VERSION 5.7 ;
  NOWIREEXTENSIONATPIN ON ;
  DIVIDERCHAR "/" ;
  BUSBITCHARS "[]" ;
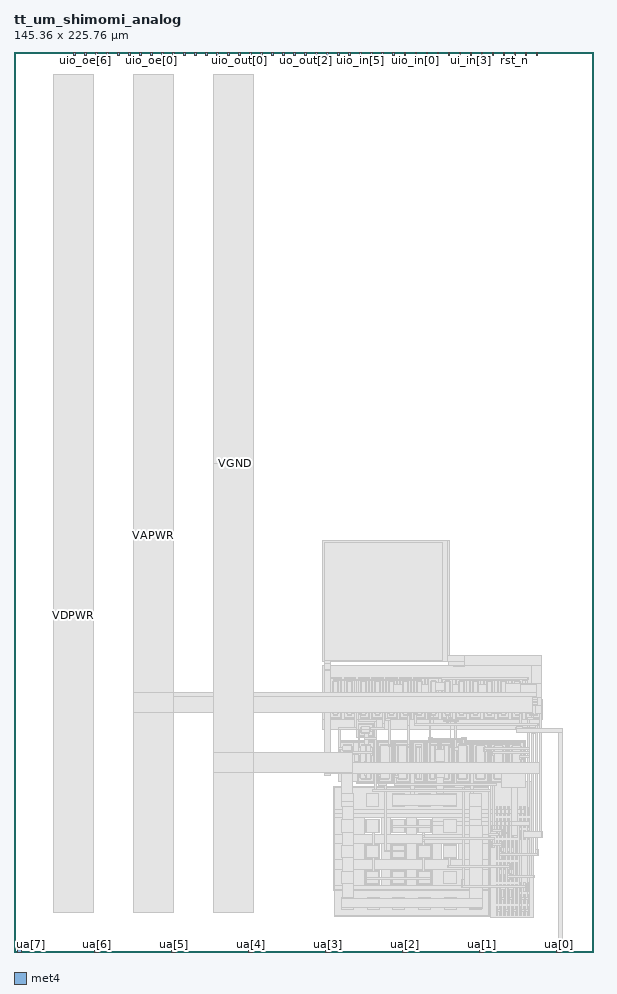
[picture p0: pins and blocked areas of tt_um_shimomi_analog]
MACRO tt_um_shimomi_analog
  CLASS BLOCK ;
  FOREIGN tt_um_shimomi_analog ;
  ORIGIN 0.000 0.000 ;
  SIZE 145.360 BY 225.760 ;
  PIN clk
    DIRECTION INPUT ;
    USE SIGNAL ;
    PORT
      LAYER met4 ;
        RECT 128.190 224.760 128.490 225.760 ;
    END
  END clk
  PIN ena
    DIRECTION INPUT ;
    USE SIGNAL ;
    PORT
      LAYER met4 ;
        RECT 130.950 224.760 131.250 225.760 ;
    END
  END ena
  PIN rst_n
    DIRECTION INPUT ;
    USE SIGNAL ;
    PORT
      LAYER met4 ;
        RECT 125.430 224.760 125.730 225.760 ;
    END
  END rst_n
  PIN ua[0]
    DIRECTION INOUT ;
    USE SIGNAL ;
    ANTENNADIFFAREA 11.599999 ;
    PORT
      LAYER met4 ;
        RECT 136.170 0.000 137.070 1.000 ;
    END
  END ua[0]
  PIN ua[1]
    DIRECTION INOUT ;
    USE SIGNAL ;
    PORT
      LAYER met4 ;
        RECT 116.850 0.000 117.750 1.000 ;
    END
  END ua[1]
  PIN ua[2]
    DIRECTION INOUT ;
    USE SIGNAL ;
    PORT
      LAYER met4 ;
        RECT 97.530 0.000 98.430 1.000 ;
    END
  END ua[2]
  PIN ua[3]
    DIRECTION INOUT ;
    USE SIGNAL ;
    PORT
      LAYER met4 ;
        RECT 78.210 0.000 79.110 1.000 ;
    END
  END ua[3]
  PIN ua[4]
    DIRECTION INOUT ;
    USE SIGNAL ;
    PORT
      LAYER met4 ;
        RECT 58.890 0.000 59.790 1.000 ;
    END
  END ua[4]
  PIN ua[5]
    DIRECTION INOUT ;
    USE SIGNAL ;
    PORT
      LAYER met4 ;
        RECT 39.570 0.000 40.470 1.000 ;
    END
  END ua[5]
  PIN ua[6]
    DIRECTION INOUT ;
    USE SIGNAL ;
    PORT
      LAYER met4 ;
        RECT 20.250 0.000 21.150 1.000 ;
    END
  END ua[6]
  PIN ua[7]
    DIRECTION INOUT ;
    USE SIGNAL ;
    PORT
      LAYER met4 ;
        RECT 0.930 0.000 1.830 1.000 ;
    END
  END ua[7]
  PIN ui_in[0]
    DIRECTION INPUT ;
    USE SIGNAL ;
    PORT
      LAYER met4 ;
        RECT 122.670 224.760 122.970 225.760 ;
    END
  END ui_in[0]
  PIN ui_in[1]
    DIRECTION INPUT ;
    USE SIGNAL ;
    PORT
      LAYER met4 ;
        RECT 119.910 224.760 120.210 225.760 ;
    END
  END ui_in[1]
  PIN ui_in[2]
    DIRECTION INPUT ;
    USE SIGNAL ;
    PORT
      LAYER met4 ;
        RECT 117.150 224.760 117.450 225.760 ;
    END
  END ui_in[2]
  PIN ui_in[3]
    DIRECTION INPUT ;
    USE SIGNAL ;
    PORT
      LAYER met4 ;
        RECT 114.390 224.760 114.690 225.760 ;
    END
  END ui_in[3]
  PIN ui_in[4]
    DIRECTION INPUT ;
    USE SIGNAL ;
    PORT
      LAYER met4 ;
        RECT 111.630 224.760 111.930 225.760 ;
    END
  END ui_in[4]
  PIN ui_in[5]
    DIRECTION INPUT ;
    USE SIGNAL ;
    PORT
      LAYER met4 ;
        RECT 108.870 224.760 109.170 225.760 ;
    END
  END ui_in[5]
  PIN ui_in[6]
    DIRECTION INPUT ;
    USE SIGNAL ;
    PORT
      LAYER met4 ;
        RECT 106.110 224.760 106.410 225.760 ;
    END
  END ui_in[6]
  PIN ui_in[7]
    DIRECTION INPUT ;
    USE SIGNAL ;
    PORT
      LAYER met4 ;
        RECT 103.350 224.760 103.650 225.760 ;
    END
  END ui_in[7]
  PIN uio_in[0]
    DIRECTION INPUT ;
    USE SIGNAL ;
    PORT
      LAYER met4 ;
        RECT 100.590 224.760 100.890 225.760 ;
    END
  END uio_in[0]
  PIN uio_in[1]
    DIRECTION INPUT ;
    USE SIGNAL ;
    PORT
      LAYER met4 ;
        RECT 97.830 224.760 98.130 225.760 ;
    END
  END uio_in[1]
  PIN uio_in[2]
    DIRECTION INPUT ;
    USE SIGNAL ;
    PORT
      LAYER met4 ;
        RECT 95.070 224.760 95.370 225.760 ;
    END
  END uio_in[2]
  PIN uio_in[3]
    DIRECTION INPUT ;
    USE SIGNAL ;
    PORT
      LAYER met4 ;
        RECT 92.310 224.760 92.610 225.760 ;
    END
  END uio_in[3]
  PIN uio_in[4]
    DIRECTION INPUT ;
    USE SIGNAL ;
    PORT
      LAYER met4 ;
        RECT 89.550 224.760 89.850 225.760 ;
    END
  END uio_in[4]
  PIN uio_in[5]
    DIRECTION INPUT ;
    USE SIGNAL ;
    PORT
      LAYER met4 ;
        RECT 86.790 224.760 87.090 225.760 ;
    END
  END uio_in[5]
  PIN uio_in[6]
    DIRECTION INPUT ;
    USE SIGNAL ;
    PORT
      LAYER met4 ;
        RECT 84.030 224.760 84.330 225.760 ;
    END
  END uio_in[6]
  PIN uio_in[7]
    DIRECTION INPUT ;
    USE SIGNAL ;
    PORT
      LAYER met4 ;
        RECT 81.270 224.760 81.570 225.760 ;
    END
  END uio_in[7]
  PIN uio_oe[0]
    DIRECTION OUTPUT ;
    USE SIGNAL ;
    PORT
      LAYER met4 ;
        RECT 34.350 224.760 34.650 225.760 ;
    END
  END uio_oe[0]
  PIN uio_oe[1]
    DIRECTION OUTPUT ;
    USE SIGNAL ;
    PORT
      LAYER met4 ;
        RECT 31.590 224.760 31.890 225.760 ;
    END
  END uio_oe[1]
  PIN uio_oe[2]
    DIRECTION OUTPUT ;
    USE SIGNAL ;
    PORT
      LAYER met4 ;
        RECT 28.830 224.760 29.130 225.760 ;
    END
  END uio_oe[2]
  PIN uio_oe[3]
    DIRECTION OUTPUT ;
    USE SIGNAL ;
    PORT
      LAYER met4 ;
        RECT 26.070 224.760 26.370 225.760 ;
    END
  END uio_oe[3]
  PIN uio_oe[4]
    DIRECTION OUTPUT ;
    USE SIGNAL ;
    PORT
      LAYER met4 ;
        RECT 23.310 224.760 23.610 225.760 ;
    END
  END uio_oe[4]
  PIN uio_oe[5]
    DIRECTION OUTPUT ;
    USE SIGNAL ;
    PORT
      LAYER met4 ;
        RECT 20.550 224.760 20.850 225.760 ;
    END
  END uio_oe[5]
  PIN uio_oe[6]
    DIRECTION OUTPUT ;
    USE SIGNAL ;
    PORT
      LAYER met4 ;
        RECT 17.790 224.760 18.090 225.760 ;
    END
  END uio_oe[6]
  PIN uio_oe[7]
    DIRECTION OUTPUT ;
    USE SIGNAL ;
    PORT
      LAYER met4 ;
        RECT 15.030 224.760 15.330 225.760 ;
    END
  END uio_oe[7]
  PIN uio_out[0]
    DIRECTION OUTPUT ;
    USE SIGNAL ;
    PORT
      LAYER met4 ;
        RECT 56.430 224.760 56.730 225.760 ;
    END
  END uio_out[0]
  PIN uio_out[1]
    DIRECTION OUTPUT ;
    USE SIGNAL ;
    PORT
      LAYER met4 ;
        RECT 53.670 224.760 53.970 225.760 ;
    END
  END uio_out[1]
  PIN uio_out[2]
    DIRECTION OUTPUT ;
    USE SIGNAL ;
    PORT
      LAYER met4 ;
        RECT 50.910 224.760 51.210 225.760 ;
    END
  END uio_out[2]
  PIN uio_out[3]
    DIRECTION OUTPUT ;
    USE SIGNAL ;
    PORT
      LAYER met4 ;
        RECT 48.150 224.760 48.450 225.760 ;
    END
  END uio_out[3]
  PIN uio_out[4]
    DIRECTION OUTPUT ;
    USE SIGNAL ;
    PORT
      LAYER met4 ;
        RECT 45.390 224.760 45.690 225.760 ;
    END
  END uio_out[4]
  PIN uio_out[5]
    DIRECTION OUTPUT ;
    USE SIGNAL ;
    PORT
      LAYER met4 ;
        RECT 42.630 224.760 42.930 225.760 ;
    END
  END uio_out[5]
  PIN uio_out[6]
    DIRECTION OUTPUT ;
    USE SIGNAL ;
    PORT
      LAYER met4 ;
        RECT 39.870 224.760 40.170 225.760 ;
    END
  END uio_out[6]
  PIN uio_out[7]
    DIRECTION OUTPUT ;
    USE SIGNAL ;
    PORT
      LAYER met4 ;
        RECT 37.110 224.760 37.410 225.760 ;
    END
  END uio_out[7]
  PIN uo_out[0]
    DIRECTION OUTPUT ;
    USE SIGNAL ;
    PORT
      LAYER met4 ;
        RECT 78.510 224.760 78.810 225.760 ;
    END
  END uo_out[0]
  PIN uo_out[1]
    DIRECTION OUTPUT ;
    USE SIGNAL ;
    PORT
      LAYER met4 ;
        RECT 75.750 224.760 76.050 225.760 ;
    END
  END uo_out[1]
  PIN uo_out[2]
    DIRECTION OUTPUT ;
    USE SIGNAL ;
    PORT
      LAYER met4 ;
        RECT 72.990 224.760 73.290 225.760 ;
    END
  END uo_out[2]
  PIN uo_out[3]
    DIRECTION OUTPUT ;
    USE SIGNAL ;
    PORT
      LAYER met4 ;
        RECT 70.230 224.760 70.530 225.760 ;
    END
  END uo_out[3]
  PIN uo_out[4]
    DIRECTION OUTPUT ;
    USE SIGNAL ;
    PORT
      LAYER met4 ;
        RECT 67.470 224.760 67.770 225.760 ;
    END
  END uo_out[4]
  PIN uo_out[5]
    DIRECTION OUTPUT ;
    USE SIGNAL ;
    PORT
      LAYER met4 ;
        RECT 64.710 224.760 65.010 225.760 ;
    END
  END uo_out[5]
  PIN uo_out[6]
    DIRECTION OUTPUT ;
    USE SIGNAL ;
    PORT
      LAYER met4 ;
        RECT 61.950 224.760 62.250 225.760 ;
    END
  END uo_out[6]
  PIN uo_out[7]
    DIRECTION OUTPUT ;
    USE SIGNAL ;
    PORT
      LAYER met4 ;
        RECT 59.190 224.760 59.490 225.760 ;
    END
  END uo_out[7]
  PIN VGND
    USE GROUND ;
    PORT
      LAYER met4 ;
        RECT 55.495 122.495 55.505 122.505 ;
    END
  END VGND
  PIN VAPWR
    ANTENNADIFFAREA 139.722000 ;
    PORT
      LAYER met4 ;
        RECT 34.995 104.495 35.005 104.505 ;
    END
  END VAPWR
  PIN VDPWR
    PORT
      LAYER met4 ;
        RECT 14.995 84.495 15.005 84.505 ;
    END
  END VDPWR
  OBS
      LAYER nwell ;
        RECT 77.410 63.230 132.410 71.760 ;
        RECT 77.410 58.260 132.490 63.230 ;
        RECT 77.410 55.760 132.410 58.260 ;
        RECT 85.910 53.760 90.490 55.760 ;
      LAYER pwell ;
        RECT 81.410 52.760 85.690 52.940 ;
        RECT 85.910 52.760 90.480 52.940 ;
        RECT 81.410 42.760 90.480 52.760 ;
        RECT 85.910 42.360 90.480 42.760 ;
        RECT 90.910 42.360 95.190 52.940 ;
        RECT 95.410 42.360 99.690 52.940 ;
        RECT 99.910 42.360 103.190 52.940 ;
        RECT 103.410 42.360 106.690 52.940 ;
        RECT 106.910 42.360 110.190 52.940 ;
        RECT 110.410 42.360 114.690 52.940 ;
        RECT 114.910 42.360 119.190 52.940 ;
        RECT 119.410 42.760 123.690 52.940 ;
        RECT 123.910 42.760 128.190 52.940 ;
        RECT 80.240 40.695 119.140 41.460 ;
        RECT 80.240 35.525 81.005 40.695 ;
        RECT 86.175 35.525 87.445 40.695 ;
        RECT 92.615 35.525 93.885 40.695 ;
        RECT 99.055 35.525 100.325 40.695 ;
        RECT 105.495 35.525 106.765 40.695 ;
        RECT 111.935 35.525 113.205 40.695 ;
        RECT 118.375 35.525 119.140 40.695 ;
        RECT 80.240 34.940 119.140 35.525 ;
        RECT 80.240 34.195 119.190 34.940 ;
        RECT 80.240 34.190 106.775 34.195 ;
        RECT 80.240 34.175 87.445 34.190 ;
        RECT 80.240 29.005 81.005 34.175 ;
        RECT 86.175 29.020 87.445 34.175 ;
        RECT 92.615 29.020 93.885 34.190 ;
        RECT 99.055 29.020 100.325 34.190 ;
        RECT 105.495 29.025 106.775 34.190 ;
        RECT 111.945 34.175 119.190 34.195 ;
        RECT 111.945 29.025 113.255 34.175 ;
        RECT 105.495 29.020 113.255 29.025 ;
        RECT 86.175 29.005 113.255 29.020 ;
        RECT 118.425 29.005 119.190 34.175 ;
        RECT 80.240 27.750 119.190 29.005 ;
        RECT 80.240 27.735 87.445 27.750 ;
        RECT 80.240 22.565 81.005 27.735 ;
        RECT 86.175 22.580 87.445 27.735 ;
        RECT 92.615 22.580 93.895 27.750 ;
        RECT 99.065 22.580 100.335 27.750 ;
        RECT 105.505 27.745 119.190 27.750 ;
        RECT 105.505 22.580 106.775 27.745 ;
        RECT 86.175 22.575 106.775 22.580 ;
        RECT 111.945 27.735 119.190 27.745 ;
        RECT 111.945 22.575 113.255 27.735 ;
        RECT 86.175 22.565 113.255 22.575 ;
        RECT 118.425 22.565 119.190 27.735 ;
        RECT 80.240 21.310 119.190 22.565 ;
        RECT 80.240 21.295 87.445 21.310 ;
        RECT 80.240 16.125 81.005 21.295 ;
        RECT 86.175 16.140 87.445 21.295 ;
        RECT 92.615 16.140 93.885 21.310 ;
        RECT 99.055 16.140 100.325 21.310 ;
        RECT 105.495 21.295 119.190 21.310 ;
        RECT 105.495 16.140 106.775 21.295 ;
        RECT 86.175 16.125 106.775 16.140 ;
        RECT 111.945 16.125 113.255 21.295 ;
        RECT 118.425 16.125 119.190 21.295 ;
        RECT 80.240 15.360 119.190 16.125 ;
        RECT 80.290 14.845 119.190 15.360 ;
        RECT 80.290 9.675 81.055 14.845 ;
        RECT 86.225 9.675 87.495 14.845 ;
        RECT 92.665 9.675 93.935 14.845 ;
        RECT 99.105 9.675 100.375 14.845 ;
        RECT 105.545 9.675 106.815 14.845 ;
        RECT 111.985 9.675 113.255 14.845 ;
        RECT 118.425 9.675 119.190 14.845 ;
        RECT 80.290 8.910 119.190 9.675 ;
        RECT 119.410 8.760 130.410 42.760 ;
      LAYER li1 ;
        RECT 79.300 68.670 82.100 68.840 ;
        RECT 79.300 58.820 79.470 68.670 ;
        RECT 80.200 67.980 81.200 68.150 ;
        RECT 79.970 59.725 80.140 67.765 ;
        RECT 81.260 59.725 81.430 67.765 ;
        RECT 80.200 59.340 81.200 59.510 ;
        RECT 81.930 58.820 82.100 68.670 ;
        RECT 79.300 58.650 82.100 58.820 ;
        RECT 82.800 68.670 85.600 68.840 ;
        RECT 82.800 58.820 82.970 68.670 ;
        RECT 83.700 67.980 84.700 68.150 ;
        RECT 83.470 59.725 83.640 67.765 ;
        RECT 84.760 59.725 84.930 67.765 ;
        RECT 83.700 59.340 84.700 59.510 ;
        RECT 85.430 58.820 85.600 68.670 ;
        RECT 82.800 58.650 85.600 58.820 ;
        RECT 86.300 68.670 89.100 68.840 ;
        RECT 86.300 58.820 86.470 68.670 ;
        RECT 87.200 67.980 88.200 68.150 ;
        RECT 86.970 59.725 87.140 67.765 ;
        RECT 88.260 59.725 88.430 67.765 ;
        RECT 87.200 59.340 88.200 59.510 ;
        RECT 88.930 58.820 89.100 68.670 ;
        RECT 86.300 58.650 89.100 58.820 ;
        RECT 89.800 68.670 92.600 68.840 ;
        RECT 89.800 58.820 89.970 68.670 ;
        RECT 90.700 67.980 91.700 68.150 ;
        RECT 90.470 59.725 90.640 67.765 ;
        RECT 91.760 59.725 91.930 67.765 ;
        RECT 90.700 59.340 91.700 59.510 ;
        RECT 92.430 58.820 92.600 68.670 ;
        RECT 89.800 58.650 92.600 58.820 ;
        RECT 93.300 68.670 96.100 68.840 ;
        RECT 93.300 58.820 93.470 68.670 ;
        RECT 94.200 67.980 95.200 68.150 ;
        RECT 93.970 59.725 94.140 67.765 ;
        RECT 95.260 59.725 95.430 67.765 ;
        RECT 94.200 59.340 95.200 59.510 ;
        RECT 95.930 58.820 96.100 68.670 ;
        RECT 93.300 58.650 96.100 58.820 ;
        RECT 96.800 68.670 99.600 68.840 ;
        RECT 96.800 58.820 96.970 68.670 ;
        RECT 97.700 67.980 98.700 68.150 ;
        RECT 97.470 59.725 97.640 67.765 ;
        RECT 98.760 59.725 98.930 67.765 ;
        RECT 97.700 59.340 98.700 59.510 ;
        RECT 99.430 58.820 99.600 68.670 ;
        RECT 96.800 58.650 99.600 58.820 ;
        RECT 100.300 68.670 103.100 68.840 ;
        RECT 100.300 58.820 100.470 68.670 ;
        RECT 101.200 67.980 102.200 68.150 ;
        RECT 100.970 59.725 101.140 67.765 ;
        RECT 102.260 59.725 102.430 67.765 ;
        RECT 101.200 59.340 102.200 59.510 ;
        RECT 102.930 58.820 103.100 68.670 ;
        RECT 100.300 58.650 103.100 58.820 ;
        RECT 103.800 68.670 106.600 68.840 ;
        RECT 103.800 58.820 103.970 68.670 ;
        RECT 104.700 67.980 105.700 68.150 ;
        RECT 104.470 59.725 104.640 67.765 ;
        RECT 105.760 59.725 105.930 67.765 ;
        RECT 104.700 59.340 105.700 59.510 ;
        RECT 106.430 58.820 106.600 68.670 ;
        RECT 103.800 58.650 106.600 58.820 ;
        RECT 107.300 68.670 110.100 68.840 ;
        RECT 107.300 58.820 107.470 68.670 ;
        RECT 108.200 67.980 109.200 68.150 ;
        RECT 107.970 59.725 108.140 67.765 ;
        RECT 109.260 59.725 109.430 67.765 ;
        RECT 108.200 59.340 109.200 59.510 ;
        RECT 109.930 58.820 110.100 68.670 ;
        RECT 107.300 58.650 110.100 58.820 ;
        RECT 110.800 68.670 113.600 68.840 ;
        RECT 110.800 58.820 110.970 68.670 ;
        RECT 111.700 67.980 112.700 68.150 ;
        RECT 111.470 59.725 111.640 67.765 ;
        RECT 112.760 59.725 112.930 67.765 ;
        RECT 111.700 59.340 112.700 59.510 ;
        RECT 113.430 58.820 113.600 68.670 ;
        RECT 110.800 58.650 113.600 58.820 ;
        RECT 114.300 68.670 117.100 68.840 ;
        RECT 114.300 58.820 114.470 68.670 ;
        RECT 115.200 67.980 116.200 68.150 ;
        RECT 114.970 59.725 115.140 67.765 ;
        RECT 116.260 59.725 116.430 67.765 ;
        RECT 115.200 59.340 116.200 59.510 ;
        RECT 116.930 58.820 117.100 68.670 ;
        RECT 114.300 58.650 117.100 58.820 ;
        RECT 117.800 68.670 120.600 68.840 ;
        RECT 117.800 58.820 117.970 68.670 ;
        RECT 118.700 67.980 119.700 68.150 ;
        RECT 118.470 59.725 118.640 67.765 ;
        RECT 119.760 59.725 119.930 67.765 ;
        RECT 118.700 59.340 119.700 59.510 ;
        RECT 120.430 58.820 120.600 68.670 ;
        RECT 117.800 58.650 120.600 58.820 ;
        RECT 121.300 68.670 124.100 68.840 ;
        RECT 121.300 58.820 121.470 68.670 ;
        RECT 122.200 67.980 123.200 68.150 ;
        RECT 121.970 59.725 122.140 67.765 ;
        RECT 123.260 59.725 123.430 67.765 ;
        RECT 122.200 59.340 123.200 59.510 ;
        RECT 123.930 58.820 124.100 68.670 ;
        RECT 121.300 58.650 124.100 58.820 ;
        RECT 124.800 68.670 127.600 68.840 ;
        RECT 124.800 58.820 124.970 68.670 ;
        RECT 125.700 67.980 126.700 68.150 ;
        RECT 125.470 59.725 125.640 67.765 ;
        RECT 126.760 59.725 126.930 67.765 ;
        RECT 125.700 59.340 126.700 59.510 ;
        RECT 127.430 58.820 127.600 68.670 ;
        RECT 124.800 58.650 127.600 58.820 ;
        RECT 128.300 62.670 132.100 62.840 ;
        RECT 128.300 58.820 128.470 62.670 ;
        RECT 129.200 61.980 131.200 62.150 ;
        RECT 128.970 59.725 129.140 61.765 ;
        RECT 131.260 59.725 131.430 61.765 ;
        RECT 131.930 61.760 132.100 62.670 ;
        RECT 131.710 59.860 132.210 61.760 ;
        RECT 129.200 59.340 131.200 59.510 ;
        RECT 131.930 58.820 132.100 59.860 ;
        RECT 128.300 58.650 132.100 58.820 ;
        RECT 86.300 57.170 90.100 57.340 ;
        RECT 86.300 54.320 86.470 57.170 ;
        RECT 87.200 56.480 89.200 56.650 ;
        RECT 86.970 55.225 87.140 56.265 ;
        RECT 89.260 55.225 89.430 56.265 ;
        RECT 87.200 54.840 89.200 55.010 ;
        RECT 89.930 54.320 90.100 57.170 ;
        RECT 86.300 54.150 90.100 54.320 ;
        RECT 85.410 52.700 86.410 52.760 ;
        RECT 81.650 52.530 90.240 52.700 ;
        RECT 81.650 49.770 81.820 52.530 ;
        RECT 82.550 51.840 84.550 52.010 ;
        RECT 82.320 50.630 82.490 51.670 ;
        RECT 84.610 50.630 84.780 51.670 ;
        RECT 82.550 50.290 84.550 50.460 ;
        RECT 85.280 49.770 86.410 52.530 ;
        RECT 87.050 51.840 88.050 52.010 ;
        RECT 88.340 51.840 89.340 52.010 ;
        RECT 81.650 49.600 86.410 49.770 ;
        RECT 85.410 47.760 86.410 49.600 ;
        RECT 86.150 47.560 86.320 47.760 ;
        RECT 85.910 44.760 86.320 47.560 ;
        RECT 86.150 42.770 86.320 44.760 ;
        RECT 86.820 43.630 86.990 51.670 ;
        RECT 88.110 43.630 88.280 51.670 ;
        RECT 89.400 43.630 89.570 51.670 ;
        RECT 87.050 43.290 88.050 43.460 ;
        RECT 88.340 43.290 89.340 43.460 ;
        RECT 90.070 42.770 90.240 52.530 ;
        RECT 86.150 42.600 90.240 42.770 ;
        RECT 91.150 52.530 94.950 52.700 ;
        RECT 91.150 42.770 91.320 52.530 ;
        RECT 92.050 51.840 94.050 52.010 ;
        RECT 91.820 43.630 91.990 51.670 ;
        RECT 94.110 43.630 94.280 51.670 ;
        RECT 94.780 47.460 94.950 52.530 ;
        RECT 95.650 52.530 99.450 52.700 ;
        RECT 95.650 47.460 95.820 52.530 ;
        RECT 96.550 51.840 98.550 52.010 ;
        RECT 94.780 44.860 95.820 47.460 ;
        RECT 92.050 43.290 94.050 43.460 ;
        RECT 94.780 42.770 94.950 44.860 ;
        RECT 91.150 42.600 94.950 42.770 ;
        RECT 95.650 42.770 95.820 44.860 ;
        RECT 96.320 43.630 96.490 51.670 ;
        RECT 98.610 43.630 98.780 51.670 ;
        RECT 99.280 47.560 99.450 52.530 ;
        RECT 100.150 52.530 102.950 52.700 ;
        RECT 100.150 47.560 100.320 52.530 ;
        RECT 101.050 51.840 102.050 52.010 ;
        RECT 99.280 44.860 100.320 47.560 ;
        RECT 96.550 43.290 98.550 43.460 ;
        RECT 99.280 42.770 99.450 44.860 ;
        RECT 95.650 42.600 99.450 42.770 ;
        RECT 100.150 42.770 100.320 44.860 ;
        RECT 100.820 43.630 100.990 51.670 ;
        RECT 102.110 43.630 102.280 51.670 ;
        RECT 102.780 47.560 102.950 52.530 ;
        RECT 103.650 52.530 106.450 52.700 ;
        RECT 103.650 47.560 103.820 52.530 ;
        RECT 104.550 51.840 105.550 52.010 ;
        RECT 102.780 44.760 103.820 47.560 ;
        RECT 101.050 43.290 102.050 43.460 ;
        RECT 102.780 42.770 102.950 44.760 ;
        RECT 100.150 42.600 102.950 42.770 ;
        RECT 103.650 42.770 103.820 44.760 ;
        RECT 104.320 43.630 104.490 51.670 ;
        RECT 105.610 50.660 105.780 51.670 ;
        RECT 106.280 50.660 106.450 52.530 ;
        RECT 107.150 52.530 109.950 52.700 ;
        RECT 107.150 50.660 107.320 52.530 ;
        RECT 108.050 51.840 109.050 52.010 ;
        RECT 107.820 50.660 107.990 51.670 ;
        RECT 105.610 45.060 107.990 50.660 ;
        RECT 105.610 43.630 105.780 45.060 ;
        RECT 104.550 43.290 105.550 43.460 ;
        RECT 106.280 42.770 106.450 45.060 ;
        RECT 103.650 42.600 106.450 42.770 ;
        RECT 107.150 42.770 107.320 45.060 ;
        RECT 107.820 43.630 107.990 45.060 ;
        RECT 109.110 43.630 109.280 51.670 ;
        RECT 108.050 43.290 109.050 43.460 ;
        RECT 109.780 42.770 109.950 52.530 ;
        RECT 107.150 42.600 109.950 42.770 ;
        RECT 110.650 52.530 114.450 52.700 ;
        RECT 110.650 42.770 110.820 52.530 ;
        RECT 111.550 51.840 113.550 52.010 ;
        RECT 111.320 43.630 111.490 51.670 ;
        RECT 113.610 43.630 113.780 51.670 ;
        RECT 114.280 47.560 114.450 52.530 ;
        RECT 115.150 52.530 118.950 52.700 ;
        RECT 115.150 47.560 115.320 52.530 ;
        RECT 116.050 51.840 118.050 52.010 ;
        RECT 114.280 44.860 115.320 47.560 ;
        RECT 111.550 43.290 113.550 43.460 ;
        RECT 114.280 42.770 114.450 44.860 ;
        RECT 110.650 42.600 114.450 42.770 ;
        RECT 115.150 42.770 115.320 44.860 ;
        RECT 115.820 43.630 115.990 51.670 ;
        RECT 118.110 43.630 118.280 51.670 ;
        RECT 116.050 43.290 118.050 43.460 ;
        RECT 118.780 42.770 118.950 52.530 ;
        RECT 115.150 42.600 118.950 42.770 ;
        RECT 119.650 52.530 123.450 52.700 ;
        RECT 119.650 42.770 119.820 52.530 ;
        RECT 120.550 51.840 122.550 52.010 ;
        RECT 120.320 43.630 120.490 51.670 ;
        RECT 122.610 47.560 122.780 51.670 ;
        RECT 123.280 47.560 123.450 52.530 ;
        RECT 124.150 52.530 127.950 52.700 ;
        RECT 124.150 47.560 124.320 52.530 ;
        RECT 125.050 51.840 127.050 52.010 ;
        RECT 124.820 47.560 124.990 51.670 ;
        RECT 122.610 44.860 124.990 47.560 ;
        RECT 122.610 43.630 122.780 44.860 ;
        RECT 120.550 43.290 122.550 43.460 ;
        RECT 123.280 42.770 123.450 44.860 ;
        RECT 119.650 42.600 123.450 42.770 ;
        RECT 124.150 42.770 124.320 44.860 ;
        RECT 124.820 43.630 124.990 44.860 ;
        RECT 127.110 43.630 127.280 51.670 ;
        RECT 127.780 47.660 127.950 52.530 ;
        RECT 127.780 44.760 128.110 47.660 ;
        RECT 125.050 43.290 127.050 43.460 ;
        RECT 127.780 42.770 127.950 44.760 ;
        RECT 124.150 42.600 127.950 42.770 ;
        RECT 80.370 35.760 119.010 41.330 ;
        RECT 120.910 35.760 121.260 36.420 ;
        RECT 121.910 35.760 122.260 36.420 ;
        RECT 122.910 35.760 123.260 36.420 ;
        RECT 123.910 35.760 124.260 36.420 ;
        RECT 124.910 35.760 125.260 36.420 ;
        RECT 125.910 35.760 126.260 36.420 ;
        RECT 126.910 35.760 127.260 36.420 ;
        RECT 127.910 35.760 128.260 36.420 ;
        RECT 80.370 34.760 128.410 35.760 ;
        RECT 80.370 33.650 119.060 34.760 ;
        RECT 120.910 34.260 121.260 34.760 ;
        RECT 121.910 34.260 122.260 34.760 ;
        RECT 122.910 34.260 123.260 34.760 ;
        RECT 123.910 34.260 124.260 34.760 ;
        RECT 124.910 34.260 125.260 34.760 ;
        RECT 125.910 34.260 126.260 34.760 ;
        RECT 126.910 34.260 127.260 34.760 ;
        RECT 127.910 34.260 128.260 34.760 ;
        RECT 128.910 34.260 129.260 36.420 ;
        RECT 80.370 29.560 87.985 33.650 ;
        RECT 88.295 29.870 91.765 33.340 ;
        RECT 92.075 29.560 94.425 33.650 ;
        RECT 94.735 29.870 98.205 33.340 ;
        RECT 98.515 29.560 100.865 33.650 ;
        RECT 101.175 29.870 104.645 33.340 ;
        RECT 104.955 32.760 119.060 33.650 ;
        RECT 120.910 32.760 121.260 33.420 ;
        RECT 121.910 32.760 122.260 33.420 ;
        RECT 122.910 32.760 123.260 33.420 ;
        RECT 123.910 32.760 124.260 33.420 ;
        RECT 124.910 32.760 125.260 33.420 ;
        RECT 125.910 32.760 126.260 33.420 ;
        RECT 126.910 32.760 127.260 33.420 ;
        RECT 127.910 32.760 128.260 33.420 ;
        RECT 128.910 32.760 129.260 33.420 ;
        RECT 104.955 31.760 129.410 32.760 ;
        RECT 104.955 29.560 119.060 31.760 ;
        RECT 120.910 31.260 121.260 31.760 ;
        RECT 121.910 31.260 122.260 31.760 ;
        RECT 122.910 31.260 123.260 31.760 ;
        RECT 123.910 31.260 124.260 31.760 ;
        RECT 124.910 31.260 125.260 31.760 ;
        RECT 125.910 31.260 126.260 31.760 ;
        RECT 80.370 27.210 119.060 29.560 ;
        RECT 120.910 28.760 121.260 30.920 ;
        RECT 121.910 28.760 122.260 30.920 ;
        RECT 122.910 29.960 123.260 30.920 ;
        RECT 123.910 29.960 124.260 30.920 ;
        RECT 122.910 29.660 124.260 29.960 ;
        RECT 122.910 28.760 123.260 29.660 ;
        RECT 123.910 28.760 124.260 29.660 ;
        RECT 124.910 28.760 125.260 30.920 ;
        RECT 125.910 28.760 126.260 30.920 ;
        RECT 80.370 23.120 87.985 27.210 ;
        RECT 88.295 23.430 91.765 26.900 ;
        RECT 92.075 23.120 94.435 27.210 ;
        RECT 94.745 23.430 98.215 26.900 ;
        RECT 98.525 23.120 100.875 27.210 ;
        RECT 104.965 27.205 119.060 27.210 ;
        RECT 101.185 23.430 104.655 26.900 ;
        RECT 104.965 23.120 107.315 27.205 ;
        RECT 107.625 23.425 111.095 26.895 ;
        RECT 80.370 23.115 107.315 23.120 ;
        RECT 111.405 23.115 119.060 27.205 ;
        RECT 120.910 25.760 121.260 27.920 ;
        RECT 121.910 25.760 122.260 27.920 ;
        RECT 122.910 25.760 123.260 27.920 ;
        RECT 123.910 25.760 124.260 27.920 ;
        RECT 124.910 25.760 125.260 27.920 ;
        RECT 125.910 25.760 126.260 27.920 ;
        RECT 120.910 25.420 121.210 25.760 ;
        RECT 122.910 25.420 123.210 25.760 ;
        RECT 123.910 25.420 124.210 25.760 ;
        RECT 124.910 25.420 125.210 25.760 ;
        RECT 125.910 25.420 126.210 25.760 ;
        RECT 120.910 23.260 121.260 25.420 ;
        RECT 121.910 23.260 122.260 25.420 ;
        RECT 122.910 23.260 123.260 25.420 ;
        RECT 123.910 23.260 124.260 25.420 ;
        RECT 124.910 23.260 125.260 25.420 ;
        RECT 125.910 23.260 126.260 25.420 ;
        RECT 80.370 20.770 119.060 23.115 ;
        RECT 80.370 16.680 87.985 20.770 ;
        RECT 88.295 16.990 91.765 20.460 ;
        RECT 92.075 16.680 94.425 20.770 ;
        RECT 94.735 16.990 98.205 20.460 ;
        RECT 98.515 16.680 100.865 20.770 ;
        RECT 101.175 16.990 104.645 20.460 ;
        RECT 104.955 16.680 119.060 20.770 ;
        RECT 120.910 20.260 121.260 22.420 ;
        RECT 121.910 20.260 122.260 22.420 ;
        RECT 122.910 20.260 123.260 22.420 ;
        RECT 123.910 20.260 124.260 22.420 ;
        RECT 124.910 20.260 125.260 22.420 ;
        RECT 125.910 20.260 126.260 22.420 ;
        RECT 120.910 19.920 121.210 20.260 ;
        RECT 121.910 19.920 122.210 20.260 ;
        RECT 122.910 19.920 123.210 20.260 ;
        RECT 124.910 19.920 125.210 20.260 ;
        RECT 125.910 19.920 126.210 20.260 ;
        RECT 120.910 17.760 121.260 19.920 ;
        RECT 121.910 17.760 122.260 19.920 ;
        RECT 122.910 17.760 123.260 19.920 ;
        RECT 123.910 17.760 124.260 19.920 ;
        RECT 124.910 17.760 125.260 19.920 ;
        RECT 125.910 17.760 126.260 19.920 ;
        RECT 80.370 15.665 119.060 16.680 ;
        RECT 80.370 15.490 119.065 15.665 ;
        RECT 80.375 15.340 119.065 15.490 ;
        RECT 80.420 9.040 119.060 15.340 ;
        RECT 120.910 14.760 121.260 16.920 ;
        RECT 121.910 16.060 122.260 16.920 ;
        RECT 122.910 16.060 123.260 16.920 ;
        RECT 121.910 15.760 123.260 16.060 ;
        RECT 121.910 14.760 122.260 15.760 ;
        RECT 122.910 14.760 123.260 15.760 ;
        RECT 123.910 16.060 124.260 16.920 ;
        RECT 124.910 16.060 125.260 16.920 ;
        RECT 123.910 15.760 125.260 16.060 ;
        RECT 123.910 14.760 124.260 15.760 ;
        RECT 124.910 14.760 125.260 15.760 ;
        RECT 125.910 14.760 126.260 16.920 ;
        RECT 120.910 14.420 121.210 14.760 ;
        RECT 125.910 14.420 126.210 14.760 ;
        RECT 120.910 12.260 121.260 14.420 ;
        RECT 121.910 13.660 122.260 14.420 ;
        RECT 122.910 13.660 123.260 14.420 ;
        RECT 121.910 13.160 123.260 13.660 ;
        RECT 121.910 12.260 122.260 13.160 ;
        RECT 122.910 12.260 123.260 13.160 ;
        RECT 123.910 13.660 124.260 14.420 ;
        RECT 124.910 13.660 125.260 14.420 ;
        RECT 123.910 13.160 125.260 13.660 ;
        RECT 123.910 12.260 124.260 13.160 ;
        RECT 124.910 12.260 125.260 13.160 ;
        RECT 125.910 12.260 126.260 14.420 ;
        RECT 126.910 13.660 127.410 31.760 ;
        RECT 127.910 31.260 128.260 31.760 ;
        RECT 127.910 28.260 128.260 30.420 ;
        RECT 127.910 15.260 128.260 17.420 ;
        RECT 127.910 13.660 128.260 14.420 ;
        RECT 128.910 13.660 129.410 31.760 ;
        RECT 126.910 13.260 129.410 13.660 ;
        RECT 120.910 10.660 121.260 11.420 ;
        RECT 121.910 10.660 122.260 11.420 ;
        RECT 120.910 10.160 122.260 10.660 ;
        RECT 120.910 9.260 121.260 10.160 ;
        RECT 121.910 9.260 122.260 10.160 ;
        RECT 122.910 10.560 123.260 11.420 ;
        RECT 123.910 10.560 124.260 11.420 ;
        RECT 122.910 10.060 124.260 10.560 ;
        RECT 122.910 9.260 123.260 10.060 ;
        RECT 123.910 9.260 124.260 10.060 ;
        RECT 124.910 10.660 125.260 11.420 ;
        RECT 125.910 10.660 126.260 11.420 ;
        RECT 124.910 10.160 126.260 10.660 ;
        RECT 124.910 9.260 125.260 10.160 ;
        RECT 125.910 9.260 126.260 10.160 ;
        RECT 126.910 10.660 127.410 13.260 ;
        RECT 127.910 12.260 128.260 13.260 ;
        RECT 127.910 10.660 128.260 11.420 ;
        RECT 128.910 10.660 129.410 13.260 ;
        RECT 126.910 10.160 129.410 10.660 ;
        RECT 126.910 9.260 127.410 10.160 ;
        RECT 127.910 9.260 128.260 10.160 ;
        RECT 128.910 9.260 129.410 10.160 ;
      LAYER met1 ;
        RECT 77.860 70.760 79.460 72.260 ;
        RECT 77.910 47.660 79.410 70.760 ;
        RECT 100.110 68.560 114.910 68.860 ;
        RECT 100.110 68.360 102.110 68.560 ;
        RECT 80.210 68.180 102.110 68.360 ;
        RECT 111.810 68.360 114.910 68.560 ;
        RECT 111.810 68.180 126.610 68.360 ;
        RECT 127.860 68.260 128.960 68.760 ;
        RECT 80.210 68.060 102.180 68.180 ;
        RECT 80.220 67.950 81.180 68.060 ;
        RECT 83.720 67.950 84.680 68.060 ;
        RECT 79.940 60.760 80.170 67.745 ;
        RECT 79.660 60.060 80.170 60.760 ;
        RECT 79.940 59.745 80.170 60.060 ;
        RECT 81.230 63.660 81.460 67.745 ;
        RECT 83.440 63.660 83.670 67.745 ;
        RECT 81.230 61.060 83.670 63.660 ;
        RECT 81.230 59.745 81.460 61.060 ;
        RECT 83.440 59.745 83.670 61.060 ;
        RECT 84.730 60.860 84.960 67.745 ;
        RECT 84.730 59.860 85.260 60.860 ;
        RECT 84.730 59.745 84.960 59.860 ;
        RECT 80.220 59.310 81.180 59.540 ;
        RECT 83.720 59.310 84.680 59.540 ;
        RECT 85.410 56.260 85.910 68.060 ;
        RECT 87.220 67.950 88.180 68.060 ;
        RECT 90.720 67.950 91.680 68.060 ;
        RECT 94.220 67.950 95.180 68.060 ;
        RECT 97.720 67.950 98.680 68.060 ;
        RECT 101.220 67.950 102.180 68.060 ;
        RECT 104.720 67.950 105.680 68.180 ;
        RECT 108.220 67.950 109.180 68.180 ;
        RECT 111.720 68.060 126.680 68.180 ;
        RECT 111.720 67.950 112.680 68.060 ;
        RECT 115.220 67.950 116.180 68.060 ;
        RECT 118.720 67.950 119.680 68.060 ;
        RECT 122.220 67.950 123.180 68.060 ;
        RECT 125.720 67.950 126.680 68.060 ;
        RECT 86.940 60.860 87.170 67.745 ;
        RECT 86.360 59.860 87.170 60.860 ;
        RECT 86.410 59.745 87.170 59.860 ;
        RECT 88.230 63.660 88.460 67.745 ;
        RECT 90.440 63.660 90.670 67.745 ;
        RECT 88.230 61.060 90.670 63.660 ;
        RECT 88.230 59.745 88.460 61.060 ;
        RECT 90.440 59.745 90.670 61.060 ;
        RECT 91.730 60.760 91.960 67.745 ;
        RECT 92.360 61.260 93.460 63.260 ;
        RECT 91.730 60.060 92.260 60.760 ;
        RECT 91.730 59.745 91.960 60.060 ;
        RECT 86.410 59.660 87.010 59.745 ;
        RECT 86.410 58.260 86.910 59.660 ;
        RECT 87.220 59.310 88.180 59.540 ;
        RECT 90.720 59.310 91.680 59.540 ;
        RECT 86.410 57.760 90.910 58.260 ;
        RECT 87.220 56.450 89.180 56.680 ;
        RECT 81.410 55.760 85.910 56.260 ;
        RECT 89.360 56.245 89.960 56.260 ;
        RECT 81.410 51.260 81.910 55.760 ;
        RECT 86.940 55.560 87.170 56.245 ;
        RECT 86.410 55.245 87.170 55.560 ;
        RECT 89.230 55.260 89.960 56.245 ;
        RECT 89.230 55.245 89.460 55.260 ;
        RECT 86.410 55.160 87.010 55.245 ;
        RECT 82.570 51.810 84.530 52.040 ;
        RECT 86.410 51.660 86.710 55.160 ;
        RECT 87.220 54.810 89.180 55.040 ;
        RECT 87.910 53.760 88.910 54.810 ;
        RECT 90.410 53.760 90.910 57.760 ;
        RECT 92.410 57.260 92.910 61.260 ;
        RECT 93.940 60.510 94.170 67.745 ;
        RECT 93.295 60.015 94.170 60.510 ;
        RECT 93.295 58.540 93.790 60.015 ;
        RECT 93.940 59.745 94.170 60.015 ;
        RECT 95.230 67.160 95.460 67.745 ;
        RECT 97.440 67.160 97.670 67.745 ;
        RECT 95.230 60.360 97.670 67.160 ;
        RECT 95.230 59.745 95.460 60.360 ;
        RECT 97.440 59.745 97.670 60.360 ;
        RECT 98.730 59.910 98.960 67.745 ;
        RECT 100.940 60.260 101.170 67.745 ;
        RECT 98.585 59.885 98.960 59.910 ;
        RECT 98.585 59.540 99.235 59.885 ;
        RECT 94.220 59.310 95.180 59.540 ;
        RECT 97.720 59.310 99.235 59.540 ;
        RECT 93.295 58.045 94.410 58.540 ;
        RECT 92.360 55.760 92.960 57.260 ;
        RECT 87.910 53.260 90.910 53.760 ;
        RECT 87.910 52.160 88.910 53.260 ;
        RECT 87.710 52.040 88.910 52.160 ;
        RECT 87.070 51.860 89.320 52.040 ;
        RECT 87.070 51.810 88.030 51.860 ;
        RECT 88.360 51.810 89.320 51.860 ;
        RECT 88.410 51.760 88.910 51.810 ;
        RECT 86.410 51.650 86.910 51.660 ;
        RECT 82.290 51.260 82.520 51.650 ;
        RECT 81.410 50.760 82.520 51.260 ;
        RECT 82.290 50.650 82.520 50.760 ;
        RECT 84.580 51.560 84.810 51.650 ;
        RECT 84.580 50.650 85.010 51.560 ;
        RECT 86.410 51.260 87.020 51.650 ;
        RECT 82.570 50.260 84.530 50.490 ;
        RECT 82.660 49.760 84.260 50.260 ;
        RECT 84.710 47.660 85.010 50.650 ;
        RECT 86.360 49.260 87.020 51.260 ;
        RECT 77.860 44.760 85.060 47.660 ;
        RECT 85.880 47.560 86.340 47.620 ;
        RECT 85.860 44.760 86.360 47.560 ;
        RECT 77.910 44.260 79.410 44.760 ;
        RECT 82.210 39.635 85.010 44.760 ;
        RECT 85.880 44.700 86.340 44.760 ;
        RECT 86.790 43.650 87.020 49.260 ;
        RECT 88.080 47.760 88.310 51.650 ;
        RECT 89.370 51.260 89.600 51.650 ;
        RECT 89.360 49.260 89.960 51.260 ;
        RECT 87.860 44.260 88.460 47.760 ;
        RECT 88.080 43.650 88.310 44.260 ;
        RECT 89.370 43.650 89.600 49.260 ;
        RECT 87.070 43.260 88.030 43.490 ;
        RECT 88.360 43.260 89.320 43.490 ;
        RECT 90.410 40.760 90.910 53.260 ;
        RECT 93.915 52.060 94.410 58.045 ;
        RECT 98.685 56.830 99.235 59.310 ;
        RECT 100.410 59.745 101.170 60.260 ;
        RECT 102.230 67.160 102.460 67.745 ;
        RECT 102.230 60.260 103.960 67.160 ;
        RECT 102.230 59.745 102.460 60.260 ;
        RECT 104.440 59.960 104.670 67.745 ;
        RECT 104.210 59.745 104.670 59.960 ;
        RECT 105.730 67.460 105.960 67.745 ;
        RECT 107.940 67.460 108.170 67.745 ;
        RECT 105.730 65.560 108.170 67.460 ;
        RECT 105.730 59.745 105.960 65.560 ;
        RECT 107.940 59.745 108.170 65.560 ;
        RECT 109.230 59.960 109.460 67.745 ;
        RECT 111.440 67.160 111.670 67.745 ;
        RECT 109.960 60.260 111.670 67.160 ;
        RECT 109.230 59.745 109.610 59.960 ;
        RECT 111.440 59.745 111.670 60.260 ;
        RECT 112.730 60.660 112.960 67.745 ;
        RECT 114.940 60.660 115.170 67.745 ;
        RECT 112.730 59.960 115.170 60.660 ;
        RECT 112.730 59.745 112.960 59.960 ;
        RECT 114.940 59.745 115.170 59.960 ;
        RECT 116.230 67.160 116.460 67.745 ;
        RECT 118.440 67.160 118.670 67.745 ;
        RECT 116.230 61.060 118.670 67.160 ;
        RECT 116.230 59.745 116.460 61.060 ;
        RECT 118.440 59.745 118.670 61.060 ;
        RECT 119.730 60.660 119.960 67.745 ;
        RECT 121.940 60.660 122.170 67.745 ;
        RECT 119.730 59.960 122.170 60.660 ;
        RECT 119.730 59.745 119.960 59.960 ;
        RECT 121.940 59.745 122.170 59.960 ;
        RECT 123.230 67.160 123.460 67.745 ;
        RECT 125.440 67.160 125.670 67.745 ;
        RECT 123.230 61.060 125.670 67.160 ;
        RECT 123.230 59.745 123.460 61.060 ;
        RECT 125.440 59.745 125.670 61.060 ;
        RECT 126.730 60.660 126.960 67.745 ;
        RECT 128.410 61.760 128.910 68.260 ;
        RECT 129.220 61.950 131.180 62.180 ;
        RECT 131.680 61.760 132.240 61.820 ;
        RECT 126.730 59.960 127.560 60.660 ;
        RECT 126.730 59.745 127.410 59.960 ;
        RECT 128.360 59.760 129.460 61.760 ;
        RECT 130.860 60.260 132.240 61.760 ;
        RECT 130.860 59.760 132.410 60.260 ;
        RECT 128.940 59.745 129.170 59.760 ;
        RECT 100.410 59.660 101.010 59.745 ;
        RECT 104.210 59.710 104.635 59.745 ;
        RECT 100.410 57.260 100.910 59.660 ;
        RECT 101.220 59.310 102.180 59.540 ;
        RECT 93.915 52.040 98.410 52.060 ;
        RECT 98.690 52.045 99.230 56.830 ;
        RECT 100.360 56.760 101.960 57.260 ;
        RECT 104.210 53.760 104.410 59.710 ;
        RECT 104.720 59.310 105.680 59.540 ;
        RECT 108.220 59.310 109.180 59.540 ;
        RECT 105.110 57.260 105.310 59.310 ;
        RECT 108.610 58.260 108.910 59.310 ;
        RECT 107.860 57.760 108.960 58.260 ;
        RECT 108.610 57.560 108.910 57.760 ;
        RECT 104.860 56.760 105.560 57.260 ;
        RECT 103.860 53.260 104.960 53.760 ;
        RECT 92.070 51.860 98.530 52.040 ;
        RECT 98.690 51.960 99.235 52.045 ;
        RECT 92.070 51.810 94.410 51.860 ;
        RECT 96.570 51.810 98.530 51.860 ;
        RECT 91.790 44.460 92.020 51.650 ;
        RECT 93.915 51.600 94.410 51.810 ;
        RECT 98.780 51.650 99.235 51.960 ;
        RECT 100.810 51.650 102.310 52.060 ;
        RECT 91.310 44.110 92.020 44.460 ;
        RECT 91.320 43.650 92.020 44.110 ;
        RECT 94.080 43.650 94.310 51.600 ;
        RECT 94.780 47.460 95.740 47.520 ;
        RECT 94.760 44.860 95.760 47.460 ;
        RECT 94.780 44.800 95.740 44.860 ;
        RECT 96.290 44.260 96.520 51.650 ;
        RECT 95.410 43.760 96.520 44.260 ;
        RECT 91.320 43.610 91.860 43.650 ;
        RECT 91.320 42.180 91.655 43.610 ;
        RECT 92.070 43.260 94.030 43.490 ;
        RECT 95.410 42.260 95.910 43.760 ;
        RECT 96.290 43.650 96.520 43.760 ;
        RECT 98.580 51.355 99.235 51.650 ;
        RECT 100.790 51.360 102.310 51.650 ;
        RECT 104.210 51.650 104.410 53.260 ;
        RECT 109.410 52.160 109.610 59.745 ;
        RECT 111.720 59.310 112.680 59.540 ;
        RECT 115.220 59.310 116.180 59.540 ;
        RECT 118.720 59.310 119.680 59.540 ;
        RECT 122.220 59.310 123.180 59.540 ;
        RECT 125.720 59.310 126.680 59.540 ;
        RECT 110.360 57.760 111.460 58.260 ;
        RECT 104.910 52.040 109.610 52.160 ;
        RECT 104.570 51.860 109.610 52.040 ;
        RECT 104.570 51.810 105.530 51.860 ;
        RECT 108.070 51.810 109.030 51.860 ;
        RECT 109.410 51.660 109.610 51.860 ;
        RECT 109.260 51.650 109.610 51.660 ;
        RECT 104.210 51.360 104.520 51.650 ;
        RECT 98.580 43.650 98.810 51.355 ;
        RECT 99.380 47.560 100.340 47.620 ;
        RECT 99.360 46.560 100.360 47.560 ;
        RECT 99.360 44.860 100.410 46.560 ;
        RECT 99.380 44.800 100.410 44.860 ;
        RECT 96.570 43.260 98.530 43.490 ;
        RECT 91.320 41.845 93.375 42.180 ;
        RECT 89.860 40.260 91.460 40.760 ;
        RECT 82.065 37.860 85.115 39.635 ;
        RECT 82.065 36.585 85.210 37.860 ;
        RECT 88.505 36.585 91.555 39.635 ;
        RECT 82.310 33.115 85.210 36.585 ;
        RECT 82.065 30.065 85.210 33.115 ;
        RECT 88.505 30.080 91.555 33.130 ;
        RECT 82.310 26.675 85.210 30.065 ;
        RECT 89.910 26.690 90.410 30.080 ;
        RECT 82.065 23.625 85.210 26.675 ;
        RECT 88.505 23.640 91.555 26.690 ;
        RECT 93.045 25.470 93.365 41.845 ;
        RECT 95.360 41.760 96.960 42.260 ;
        RECT 94.945 39.560 97.995 39.635 ;
        RECT 99.410 39.560 100.410 44.800 ;
        RECT 100.790 43.650 101.020 51.360 ;
        RECT 101.710 47.560 102.310 51.360 ;
        RECT 102.780 47.560 103.740 47.620 ;
        RECT 101.660 44.960 102.360 47.560 ;
        RECT 101.710 43.490 102.310 44.960 ;
        RECT 102.760 44.760 103.760 47.560 ;
        RECT 102.780 44.700 103.740 44.760 ;
        RECT 104.290 43.650 104.520 51.360 ;
        RECT 105.580 50.760 105.810 51.650 ;
        RECT 107.790 50.760 108.020 51.650 ;
        RECT 105.580 44.760 108.020 50.760 ;
        RECT 105.580 43.650 105.810 44.760 ;
        RECT 106.010 43.650 108.020 44.760 ;
        RECT 109.080 51.360 109.610 51.650 ;
        RECT 109.080 43.650 109.310 51.360 ;
        RECT 110.410 51.260 110.910 57.760 ;
        RECT 126.910 56.260 127.410 59.745 ;
        RECT 129.910 59.540 130.410 59.760 ;
        RECT 131.230 59.745 131.460 59.760 ;
        RECT 129.220 59.310 131.180 59.540 ;
        RECT 129.910 58.760 130.410 59.310 ;
        RECT 128.910 58.260 130.410 58.760 ;
        RECT 125.860 55.760 127.460 56.260 ;
        RECT 112.360 53.260 113.460 53.760 ;
        RECT 112.510 52.360 113.010 53.260 ;
        RECT 111.810 52.040 127.110 52.360 ;
        RECT 111.570 51.960 127.110 52.040 ;
        RECT 111.570 51.810 113.530 51.960 ;
        RECT 116.070 51.810 118.030 51.960 ;
        RECT 120.570 51.810 122.530 51.960 ;
        RECT 125.070 51.810 127.030 51.960 ;
        RECT 111.290 51.260 111.520 51.650 ;
        RECT 110.410 50.460 111.520 51.260 ;
        RECT 110.410 45.260 110.910 50.460 ;
        RECT 111.290 45.260 111.520 50.460 ;
        RECT 110.410 44.760 111.520 45.260 ;
        RECT 101.070 43.360 102.310 43.490 ;
        RECT 101.070 43.260 102.030 43.360 ;
        RECT 104.570 43.260 105.530 43.490 ;
        RECT 106.010 39.660 107.810 43.650 ;
        RECT 108.070 43.260 109.030 43.490 ;
        RECT 110.410 41.760 110.910 44.760 ;
        RECT 111.290 43.650 111.520 44.760 ;
        RECT 113.580 47.560 113.810 51.650 ;
        RECT 115.790 50.660 116.020 51.650 ;
        RECT 118.080 51.260 118.310 51.650 ;
        RECT 115.790 48.060 116.060 50.660 ;
        RECT 117.860 50.260 118.460 51.260 ;
        RECT 120.290 50.260 120.520 51.650 ;
        RECT 114.280 47.560 115.240 47.620 ;
        RECT 115.790 47.560 116.020 48.060 ;
        RECT 113.580 44.860 116.020 47.560 ;
        RECT 113.580 43.650 113.810 44.860 ;
        RECT 114.280 44.800 115.310 44.860 ;
        RECT 111.570 43.260 113.530 43.490 ;
        RECT 110.410 41.260 112.910 41.760 ;
        RECT 106.010 39.635 107.910 39.660 ;
        RECT 101.385 39.560 104.435 39.635 ;
        RECT 106.010 39.560 110.875 39.635 ;
        RECT 94.945 36.860 110.875 39.560 ;
        RECT 94.945 36.585 97.995 36.860 ;
        RECT 101.385 36.585 104.435 36.860 ;
        RECT 107.825 36.585 110.875 36.860 ;
        RECT 94.945 31.760 97.995 33.130 ;
        RECT 101.385 31.760 104.435 33.130 ;
        RECT 94.945 31.260 104.435 31.760 ;
        RECT 94.945 30.080 97.995 31.260 ;
        RECT 101.385 30.080 104.435 31.260 ;
        RECT 107.835 30.085 110.885 33.135 ;
        RECT 102.410 29.260 102.910 30.080 ;
        RECT 102.360 27.760 102.960 29.260 ;
        RECT 102.410 26.690 102.910 27.760 ;
        RECT 94.955 25.470 98.005 26.690 ;
        RECT 93.045 25.150 98.005 25.470 ;
        RECT 94.955 23.640 98.005 25.150 ;
        RECT 101.395 23.640 104.445 26.690 ;
        RECT 82.310 20.235 85.210 23.625 ;
        RECT 89.910 20.250 90.410 23.640 ;
        RECT 102.410 20.250 102.910 23.640 ;
        RECT 107.835 23.635 110.885 26.685 ;
        RECT 108.910 21.760 109.410 23.635 ;
        RECT 108.860 21.260 110.460 21.760 ;
        RECT 82.065 17.185 85.210 20.235 ;
        RECT 88.505 18.760 91.555 20.250 ;
        RECT 94.945 18.760 97.995 20.250 ;
        RECT 101.385 18.760 104.435 20.250 ;
        RECT 88.505 18.260 104.435 18.760 ;
        RECT 88.505 17.200 91.555 18.260 ;
        RECT 94.945 17.200 97.995 18.260 ;
        RECT 101.385 17.200 104.435 18.260 ;
        RECT 107.835 17.185 110.885 20.235 ;
        RECT 112.410 18.260 112.910 41.260 ;
        RECT 114.610 39.635 115.310 44.800 ;
        RECT 115.790 43.650 116.020 44.860 ;
        RECT 118.080 43.650 118.310 50.260 ;
        RECT 119.860 49.260 120.520 50.260 ;
        RECT 120.290 43.650 120.520 49.260 ;
        RECT 122.580 47.560 122.810 51.650 ;
        RECT 124.790 50.760 125.020 51.650 ;
        RECT 124.790 48.160 125.060 50.760 ;
        RECT 127.080 49.260 127.310 51.650 ;
        RECT 126.860 48.260 127.460 49.260 ;
        RECT 123.380 47.560 124.240 47.620 ;
        RECT 124.790 47.560 125.020 48.160 ;
        RECT 122.580 44.860 125.020 47.560 ;
        RECT 122.580 43.650 122.810 44.860 ;
        RECT 124.790 43.650 125.020 44.860 ;
        RECT 127.080 43.650 127.310 48.260 ;
        RECT 127.780 47.660 128.140 47.720 ;
        RECT 127.760 44.760 128.160 47.660 ;
        RECT 127.780 44.700 128.140 44.760 ;
        RECT 116.070 43.260 118.030 43.490 ;
        RECT 120.570 43.260 122.530 43.490 ;
        RECT 125.070 43.260 127.030 43.490 ;
        RECT 119.860 41.760 121.060 42.260 ;
        RECT 118.360 40.260 119.460 40.760 ;
        RECT 114.265 36.585 117.315 39.635 ;
        RECT 114.310 33.115 117.310 36.585 ;
        RECT 114.310 31.660 117.365 33.115 ;
        RECT 82.310 13.785 85.210 17.185 ;
        RECT 112.360 16.260 112.960 18.260 ;
        RECT 82.115 13.460 85.210 13.785 ;
        RECT 88.555 13.460 91.605 13.785 ;
        RECT 94.995 13.460 98.045 13.785 ;
        RECT 101.435 13.460 104.485 13.785 ;
        RECT 107.875 13.460 110.925 13.785 ;
        RECT 114.310 13.460 117.410 31.660 ;
        RECT 118.910 29.760 119.410 40.260 ;
        RECT 119.910 31.760 120.410 41.760 ;
        RECT 123.860 41.260 126.460 42.260 ;
        RECT 120.960 34.285 121.210 36.390 ;
        RECT 121.960 34.285 122.210 36.390 ;
        RECT 122.960 34.285 123.210 36.390 ;
        RECT 123.960 34.285 124.210 36.390 ;
        RECT 119.860 30.260 120.460 31.760 ;
        RECT 120.960 31.290 121.210 33.395 ;
        RECT 121.960 31.290 122.210 33.395 ;
        RECT 122.960 31.290 123.210 33.395 ;
        RECT 123.960 31.290 124.210 33.395 ;
        RECT 124.910 32.760 126.410 41.260 ;
        RECT 126.960 34.285 127.210 36.390 ;
        RECT 127.960 34.285 128.210 36.390 ;
        RECT 128.910 36.260 129.410 58.260 ;
        RECT 129.860 56.760 131.460 57.260 ;
        RECT 129.860 54.760 130.460 56.260 ;
        RECT 128.960 34.285 129.210 36.260 ;
        RECT 126.960 32.760 127.210 33.395 ;
        RECT 127.960 32.760 128.210 33.395 ;
        RECT 128.960 32.760 129.210 33.395 ;
        RECT 124.910 31.760 129.410 32.760 ;
        RECT 120.960 29.760 121.210 30.890 ;
        RECT 121.960 30.760 122.210 30.890 ;
        RECT 118.910 29.260 121.410 29.760 ;
        RECT 121.860 29.260 122.460 30.760 ;
        RECT 122.960 29.960 123.210 30.890 ;
        RECT 123.960 29.960 124.210 30.890 ;
        RECT 122.960 29.660 124.210 29.960 ;
        RECT 120.960 28.785 121.210 29.260 ;
        RECT 121.960 28.785 122.210 29.260 ;
        RECT 122.960 28.785 123.210 29.660 ;
        RECT 123.960 28.785 124.210 29.660 ;
        RECT 124.910 29.260 126.410 31.760 ;
        RECT 126.960 31.290 127.210 31.760 ;
        RECT 127.960 31.290 128.210 31.760 ;
        RECT 128.960 31.290 129.210 31.760 ;
        RECT 124.960 28.785 125.210 29.260 ;
        RECT 125.410 28.760 126.410 29.260 ;
        RECT 126.960 28.285 127.210 30.390 ;
        RECT 127.960 30.260 128.210 30.390 ;
        RECT 127.860 28.760 128.460 30.260 ;
        RECT 127.960 28.285 128.210 28.760 ;
        RECT 128.960 28.285 129.210 30.390 ;
        RECT 119.860 26.260 120.460 27.760 ;
        RECT 120.960 25.790 121.210 27.895 ;
        RECT 121.960 27.760 122.210 27.895 ;
        RECT 121.860 26.260 122.460 27.760 ;
        RECT 121.960 25.790 122.210 26.260 ;
        RECT 122.960 26.160 123.210 27.895 ;
        RECT 123.960 26.260 124.210 27.895 ;
        RECT 120.960 23.285 121.210 25.390 ;
        RECT 121.960 25.260 122.210 25.390 ;
        RECT 121.860 23.260 122.460 25.260 ;
        RECT 122.910 25.060 123.210 26.160 ;
        RECT 123.910 25.160 124.210 26.260 ;
        RECT 124.960 26.160 125.210 27.895 ;
        RECT 122.960 23.285 123.210 25.060 ;
        RECT 123.960 23.285 124.210 25.160 ;
        RECT 124.910 25.060 125.210 26.160 ;
        RECT 125.960 25.790 126.210 27.895 ;
        RECT 124.960 23.285 125.210 25.060 ;
        RECT 125.960 23.285 126.210 25.390 ;
        RECT 120.960 20.290 121.210 22.395 ;
        RECT 121.960 20.660 122.210 22.395 ;
        RECT 122.960 20.660 123.210 22.395 ;
        RECT 123.960 22.260 124.210 22.395 ;
        RECT 123.860 20.760 124.460 22.260 ;
        RECT 120.960 17.785 121.210 19.890 ;
        RECT 121.910 19.560 122.210 20.660 ;
        RECT 122.910 19.560 123.210 20.660 ;
        RECT 123.960 20.290 124.210 20.760 ;
        RECT 124.960 20.660 125.210 22.395 ;
        RECT 123.960 19.760 124.210 19.890 ;
        RECT 121.960 17.785 122.210 19.560 ;
        RECT 122.960 17.785 123.210 19.560 ;
        RECT 123.860 18.260 124.460 19.760 ;
        RECT 124.910 19.560 125.210 20.660 ;
        RECT 125.960 20.290 126.210 22.395 ;
        RECT 123.960 17.785 124.210 18.260 ;
        RECT 124.960 17.785 125.210 19.560 ;
        RECT 125.960 17.785 126.210 19.890 ;
        RECT 129.910 19.260 130.410 54.760 ;
        RECT 130.910 25.760 131.410 56.760 ;
        RECT 131.910 30.260 132.410 59.760 ;
        RECT 131.860 28.760 132.460 30.260 ;
        RECT 130.860 24.260 131.460 25.760 ;
        RECT 129.360 18.760 130.460 19.260 ;
        RECT 120.960 14.790 121.210 16.895 ;
        RECT 121.960 16.060 122.210 16.895 ;
        RECT 122.960 16.060 123.210 16.895 ;
        RECT 121.960 15.760 123.210 16.060 ;
        RECT 121.960 14.790 122.210 15.760 ;
        RECT 122.960 14.790 123.210 15.760 ;
        RECT 123.960 16.060 124.210 16.895 ;
        RECT 124.960 16.060 125.210 16.895 ;
        RECT 123.960 15.760 125.210 16.060 ;
        RECT 123.960 14.790 124.210 15.760 ;
        RECT 124.960 14.790 125.210 15.760 ;
        RECT 125.960 14.790 126.210 16.895 ;
        RECT 126.960 15.290 127.210 17.395 ;
        RECT 127.960 17.260 128.210 17.395 ;
        RECT 127.860 15.260 128.460 17.260 ;
        RECT 128.960 15.290 129.210 17.395 ;
        RECT 82.115 11.060 117.510 13.460 ;
        RECT 120.960 12.285 121.210 14.390 ;
        RECT 121.960 12.285 122.210 14.390 ;
        RECT 122.960 12.285 123.210 14.390 ;
        RECT 123.960 12.285 124.210 14.390 ;
        RECT 124.960 12.285 125.210 14.390 ;
        RECT 125.960 12.285 126.210 14.390 ;
        RECT 126.960 12.285 127.210 14.390 ;
        RECT 127.960 12.285 128.210 14.390 ;
        RECT 128.960 12.285 129.210 14.390 ;
        RECT 82.115 10.735 85.165 11.060 ;
        RECT 88.555 10.735 91.605 11.060 ;
        RECT 94.995 10.735 98.045 11.060 ;
        RECT 101.435 10.735 104.485 11.060 ;
        RECT 107.875 10.735 110.925 11.060 ;
        RECT 114.310 10.960 117.410 11.060 ;
        RECT 114.315 10.735 117.365 10.960 ;
        RECT 120.960 9.290 121.210 11.395 ;
        RECT 121.960 9.290 122.210 11.395 ;
        RECT 122.960 9.290 123.210 11.395 ;
        RECT 123.960 9.290 124.210 11.395 ;
        RECT 124.960 9.290 125.210 11.395 ;
        RECT 125.960 9.290 126.210 11.395 ;
        RECT 126.960 9.290 127.210 11.395 ;
        RECT 127.960 9.290 128.210 11.395 ;
        RECT 128.960 9.290 129.210 11.395 ;
      LAYER met2 ;
        RECT 110.410 74.260 112.910 74.310 ;
        RECT 77.910 70.710 79.410 72.310 ;
        RECT 110.410 71.760 132.410 74.260 ;
        RECT 110.410 71.710 112.910 71.760 ;
        RECT 107.210 68.810 128.410 68.860 ;
        RECT 107.210 68.460 128.910 68.810 ;
        RECT 107.210 67.510 107.610 68.460 ;
        RECT 127.910 68.210 128.910 68.460 ;
        RECT 81.310 63.660 83.610 63.710 ;
        RECT 88.310 63.660 90.610 63.710 ;
        RECT 95.310 63.660 97.510 67.210 ;
        RECT 102.310 63.660 103.910 67.210 ;
        RECT 105.810 65.510 108.010 67.510 ;
        RECT 129.910 67.260 132.410 71.760 ;
        RECT 110.010 63.660 111.610 67.210 ;
        RECT 116.410 63.660 118.610 67.210 ;
        RECT 123.410 63.760 132.410 67.260 ;
        RECT 123.410 63.660 125.610 63.760 ;
        RECT 81.310 61.060 125.610 63.660 ;
        RECT 131.310 61.810 132.410 63.760 ;
        RECT 81.310 61.010 83.610 61.060 ;
        RECT 88.310 61.010 90.610 61.060 ;
        RECT 79.710 60.760 80.110 60.810 ;
        RECT 84.810 60.760 85.210 60.910 ;
        RECT 86.410 60.760 87.110 60.910 ;
        RECT 91.810 60.760 92.210 60.810 ;
        RECT 79.710 60.060 92.210 60.760 ;
        RECT 95.310 60.310 97.510 61.060 ;
        RECT 102.310 60.210 103.910 61.060 ;
        RECT 110.010 60.210 111.610 61.060 ;
        RECT 116.410 61.010 118.610 61.060 ;
        RECT 123.410 61.010 125.610 61.060 ;
        RECT 112.910 60.660 115.010 60.710 ;
        RECT 119.910 60.660 122.010 60.710 ;
        RECT 126.810 60.660 127.510 60.710 ;
        RECT 79.710 60.010 80.110 60.060 ;
        RECT 84.810 59.810 85.210 60.060 ;
        RECT 86.410 59.810 87.110 60.060 ;
        RECT 91.810 60.010 92.210 60.060 ;
        RECT 112.810 59.960 127.510 60.660 ;
        RECT 112.910 59.910 115.010 59.960 ;
        RECT 119.910 59.910 122.010 59.960 ;
        RECT 126.810 59.910 127.510 59.960 ;
        RECT 128.410 59.710 129.410 61.810 ;
        RECT 130.910 59.760 132.410 61.810 ;
        RECT 130.910 59.710 131.910 59.760 ;
        RECT 107.910 58.160 108.910 58.310 ;
        RECT 110.410 58.160 111.410 58.310 ;
        RECT 107.910 57.860 111.410 58.160 ;
        RECT 107.910 57.710 108.910 57.860 ;
        RECT 108.610 57.660 108.910 57.710 ;
        RECT 110.410 57.710 111.410 57.860 ;
        RECT 110.410 57.660 111.010 57.710 ;
        RECT 89.410 56.260 89.910 56.310 ;
        RECT 92.410 56.260 92.910 57.310 ;
        RECT 100.410 57.260 101.910 57.310 ;
        RECT 104.910 57.260 105.510 57.310 ;
        RECT 129.910 57.260 131.410 57.310 ;
        RECT 100.410 56.760 131.410 57.260 ;
        RECT 100.410 56.710 101.910 56.760 ;
        RECT 104.910 56.710 105.510 56.760 ;
        RECT 129.910 56.710 131.410 56.760 ;
        RECT 126.000 56.310 127.500 56.550 ;
        RECT 89.310 55.760 92.910 56.260 ;
        RECT 89.410 55.210 89.910 55.760 ;
        RECT 92.410 55.710 92.910 55.760 ;
        RECT 125.910 56.260 127.500 56.310 ;
        RECT 129.910 56.260 130.410 56.310 ;
        RECT 125.910 55.760 130.410 56.260 ;
        RECT 125.910 55.710 127.500 55.760 ;
        RECT 126.000 54.950 127.500 55.710 ;
        RECT 129.910 54.710 130.410 55.760 ;
        RECT 103.910 53.560 104.910 53.810 ;
        RECT 112.410 53.560 113.410 53.810 ;
        RECT 103.910 53.260 113.410 53.560 ;
        RECT 103.910 53.210 104.910 53.260 ;
        RECT 112.410 53.210 113.410 53.260 ;
        RECT 82.710 50.260 84.210 50.410 ;
        RECT 86.410 50.260 86.910 51.310 ;
        RECT 89.410 50.260 89.910 51.310 ;
        RECT 117.910 51.260 118.410 51.310 ;
        RECT 105.710 50.760 107.910 50.810 ;
        RECT 82.710 49.760 89.910 50.260 ;
        RECT 82.710 49.710 84.210 49.760 ;
        RECT 86.410 49.210 86.910 49.760 ;
        RECT 89.410 49.210 89.910 49.760 ;
        RECT 105.610 47.860 107.910 50.760 ;
        RECT 117.910 50.760 129.410 51.260 ;
        RECT 117.910 50.210 118.410 50.760 ;
        RECT 119.910 50.260 120.410 50.310 ;
        RECT 119.910 49.760 129.410 50.260 ;
        RECT 119.910 49.210 120.410 49.760 ;
        RECT 126.910 49.260 127.410 49.310 ;
        RECT 126.910 48.760 129.410 49.260 ;
        RECT 126.910 48.210 127.410 48.760 ;
        RECT 77.910 47.660 85.010 47.710 ;
        RECT 87.910 47.660 88.410 47.810 ;
        RECT 105.710 47.660 107.910 47.860 ;
        RECT 127.810 47.660 128.110 47.710 ;
        RECT 77.810 44.760 131.810 47.660 ;
        RECT 77.910 44.710 85.010 44.760 ;
        RECT 85.910 44.710 86.310 44.760 ;
        RECT 87.910 44.210 88.410 44.760 ;
        RECT 102.810 44.710 103.710 44.760 ;
        RECT 105.710 44.710 107.910 44.760 ;
        RECT 95.410 42.260 96.910 42.310 ;
        RECT 119.910 42.260 121.010 42.310 ;
        RECT 95.410 41.760 121.010 42.260 ;
        RECT 95.410 41.710 96.910 41.760 ;
        RECT 119.910 41.710 121.010 41.760 ;
        RECT 122.410 41.260 128.410 44.760 ;
        RECT 123.910 41.210 126.410 41.260 ;
        RECT 89.910 40.760 91.410 40.810 ;
        RECT 118.410 40.760 119.410 40.810 ;
        RECT 89.910 40.260 119.410 40.760 ;
        RECT 89.910 40.210 91.410 40.260 ;
        RECT 118.410 40.210 119.410 40.260 ;
        RECT 119.910 30.760 120.410 31.810 ;
        RECT 121.910 30.760 122.410 30.810 ;
        RECT 119.910 30.260 122.410 30.760 ;
        RECT 119.910 30.210 120.410 30.260 ;
        RECT 102.410 28.760 102.910 29.310 ;
        RECT 121.910 29.210 122.410 30.260 ;
        RECT 127.910 30.260 128.410 30.310 ;
        RECT 131.910 30.260 132.410 30.310 ;
        RECT 127.910 28.760 132.410 30.260 ;
        RECT 102.410 28.260 120.410 28.760 ;
        RECT 127.910 28.710 128.410 28.760 ;
        RECT 131.910 28.710 132.410 28.760 ;
        RECT 102.410 27.710 102.910 28.260 ;
        RECT 119.910 27.260 120.410 28.260 ;
        RECT 121.910 27.260 122.410 27.810 ;
        RECT 119.910 26.760 122.410 27.260 ;
        RECT 119.910 26.210 120.410 26.760 ;
        RECT 121.910 26.210 122.410 26.760 ;
        RECT 121.910 24.760 122.410 25.310 ;
        RECT 130.910 24.760 131.410 25.810 ;
        RECT 121.910 24.260 131.410 24.760 ;
        RECT 121.910 23.210 122.410 24.260 ;
        RECT 130.910 24.210 131.410 24.260 ;
        RECT 108.910 21.760 110.410 21.810 ;
        RECT 123.910 21.760 124.410 22.310 ;
        RECT 108.910 21.260 124.410 21.760 ;
        RECT 108.910 21.210 110.410 21.260 ;
        RECT 123.910 20.710 124.410 21.260 ;
        RECT 123.910 19.260 124.410 19.810 ;
        RECT 129.410 19.260 130.410 19.310 ;
        RECT 123.910 18.760 130.410 19.260 ;
        RECT 112.410 16.760 112.910 18.310 ;
        RECT 123.910 18.210 124.410 18.760 ;
        RECT 129.410 18.710 130.410 18.760 ;
        RECT 127.910 16.760 128.410 17.310 ;
        RECT 112.410 16.260 128.410 16.760 ;
        RECT 112.410 16.210 112.910 16.260 ;
        RECT 127.910 15.210 128.410 16.260 ;
      LAYER met3 ;
        RECT 77.410 72.760 109.270 103.160 ;
        RECT 77.860 70.735 79.460 72.285 ;
        RECT 110.360 71.735 112.960 74.285 ;
        RECT 126.950 65.000 131.050 67.025 ;
        RECT 29.950 63.975 131.050 65.000 ;
        RECT 29.950 60.000 130.000 63.975 ;
        RECT 125.950 54.975 127.550 56.525 ;
        RECT 49.950 45.000 85.000 50.000 ;
        RECT 77.950 44.975 84.050 45.000 ;
      LAYER met4 ;
        RECT 10.000 84.505 20.000 220.000 ;
        RECT 10.000 84.495 14.995 84.505 ;
        RECT 15.005 84.495 20.000 84.505 ;
        RECT 10.000 10.000 20.000 84.495 ;
        RECT 30.000 104.505 40.000 220.000 ;
        RECT 30.000 104.495 34.995 104.505 ;
        RECT 35.005 104.495 40.000 104.505 ;
        RECT 30.000 65.005 40.000 104.495 ;
        RECT 50.000 122.505 60.000 220.000 ;
        RECT 50.000 122.495 55.495 122.505 ;
        RECT 55.505 122.495 60.000 122.505 ;
        RECT 29.995 59.995 40.005 65.005 ;
        RECT 30.000 10.000 40.000 59.995 ;
        RECT 50.000 50.005 60.000 122.495 ;
        RECT 77.805 73.155 107.415 102.765 ;
        RECT 108.770 74.260 109.250 103.100 ;
        RECT 110.405 74.260 112.915 74.265 ;
        RECT 77.910 72.265 79.410 73.155 ;
        RECT 108.770 72.820 112.915 74.260 ;
        RECT 77.905 70.755 79.415 72.265 ;
        RECT 108.910 71.760 112.915 72.820 ;
        RECT 110.405 71.755 112.915 71.760 ;
        RECT 125.995 56.000 127.505 56.505 ;
        RECT 125.995 55.000 137.500 56.000 ;
        RECT 125.995 54.995 127.505 55.000 ;
        RECT 49.995 44.995 60.005 50.005 ;
        RECT 50.000 10.000 60.000 44.995 ;
        RECT 136.500 1.000 137.500 55.000 ;
        RECT 137.070 0.500 137.500 1.000 ;
  END
END tt_um_shimomi_analog
END LIBRARY

